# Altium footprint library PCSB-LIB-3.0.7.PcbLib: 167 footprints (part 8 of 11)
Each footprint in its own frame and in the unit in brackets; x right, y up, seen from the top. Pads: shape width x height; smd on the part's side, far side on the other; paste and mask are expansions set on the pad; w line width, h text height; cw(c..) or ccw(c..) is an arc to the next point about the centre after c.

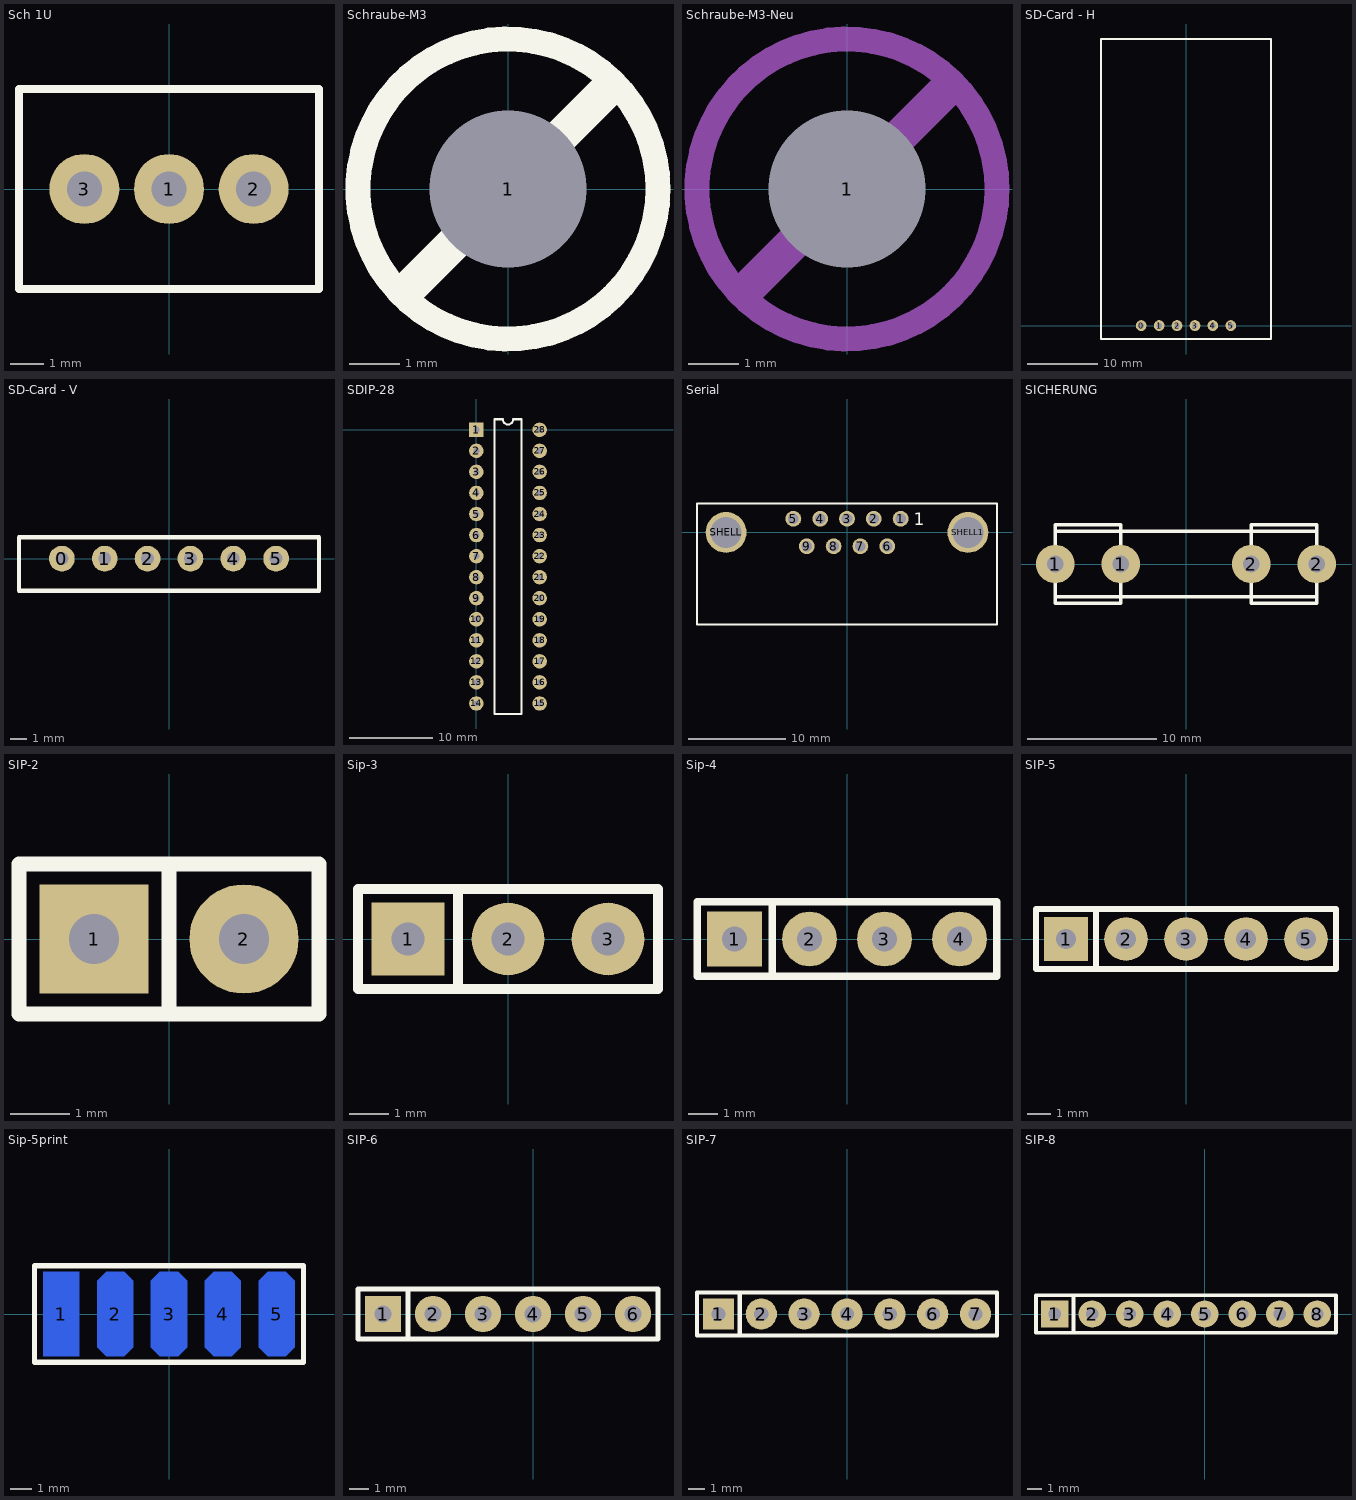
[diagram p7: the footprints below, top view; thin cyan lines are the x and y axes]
## Sch 1U [mm]
pads (3):
  round 2.1 hole 1.05: 1(0,0) 2(2.54,0) 3(-2.54,0)
Top Overlay:
  lines w0.254: -4.5,-3 4.5,-3 4.5,3 -4.5,3 -4.5,-3

## Schraube-M3 [mm] "Befestigungsschraube für Prints"
pads (1):
  round 0.75 hole 3.15 unplated: 1(0,0)
Top Overlay:
  circle w0.5: c0,0 r3
  lines w0.7: -2,-2 2,2

## Schraube-M3-Neu [mm] "Befestigungsschraube für Prints"
pads (1):
  round 0.75 hole 3.15 unplated: 1(0,0)
Mechanical 1:
  circle w0.5: c0,0 r3
  lines w0.7: -2,-2 2,2

## SD-Card - H [mil]
pads (6):
  round 60 hole 30: 0(-250,0) 1(-150,0) 2(-50,0) 3(50,0) 4(150,0) 5(250,0)
Top Overlay:
  lines w10: -475,-75 475,-75 475,1600 -475,1600 -475,-75

## SD-Card - V [mil]
pads (6):
  round 60 hole 30: 0(-250,0) 1(-150,0) 2(-50,0) 3(50,0) 4(150,0) 5(250,0)
Top Overlay:
  lines w10: -350,-75 -350,50 350,50 350,-75 -350,-75

## SDIP-28 [mm]
pads (28):
  rect 1.75x1.75 hole 0.75: 1(0,0)
  round 1.75 hole 0.75: 2(0,-2.54) 3(0,-5.08) 4(0,-7.62) 5(0,-10.16) 6(0,-12.7) 7(0,-15.24) 8(0,-17.78) 9(0,-20.32) 10(0,-22.86) 11(0,-25.4) 12(0,-27.94) 13(0,-30.48) 14(0,-33.02) 15(7.62,-33.02) 16(7.62,-30.48) 17(7.62,-27.94) 18(7.62,-25.4) 19(7.62,-22.86) 20(7.62,-20.32) 21(7.62,-17.78) 22(7.62,-15.24) 23(7.62,-12.7) 24(7.62,-10.16) 25(7.62,-7.62) 26(7.62,-5.08) 27(7.62,-2.54) 28(7.62,0)
Top Overlay:
  lines w0.254: 2.159,-34.29 2.159,1.27 3.175,1.27 ccw(c3.81,1.27) 4.445,1.27 5.461,1.27 5.461,-34.29 2.159,-34.29

## Serial [mm]
pads (11):
  round 1.635 hole 1.09: 1(5.54,1.42) 2(2.77,1.42) 3(0,1.42) 4(-2.77,1.42) 5(-5.54,1.42) 6(4.155,-1.42) 7(1.385,-1.42) 8(-1.385,-1.42) 9(-4.155,-1.42)
  round 4.216 hole 3.2: SHELL(-12.5,0) SHELL1(12.5,0)
Top Overlay:
  lines w0.2: -15.5,-9.52 15.5,-9.52 15.5,3 -15.5,3 -15.5,-9.52
  text "1" at 6.915,0.735 h1.27
Mechanical 13:
  text "1" at 6.915,0.735 h1.27

## SICHERUNG [mm]
pads (4):
  round 3 hole 1.3: 1(-10.163,0.008) 1(-5.083,0.008) 2(5.077,0.008) 2(10.157,0.008)
Top Overlay:
  lines w0.254: -10.163,-2.532 -10.163,-3.04 -5.083,-3.04 -5.083,-2.532 -5.083,2.548 -5.083,3.056 -10.163,3.056 -10.163,2.548 ; -10.163,-2.532 10.157,-2.532 ; -10.163,-2.532 -10.163,2.548 ; -10.163,2.548 10.157,2.548 ; 10.157,-2.532 10.157,-3.04 5.077,-3.04 5.077,-2.532 5.077,2.548 5.077,3.056 10.157,3.056 10.157,2.548 ; 10.157,-2.532 10.157,2.548

## SIP-2 [mm]
pads (2):
  rect 1.85x1.85 hole 0.85: 1(-1.27,0)
  round 1.85 hole 0.85: 2(1.27,0)
Top Overlay:
  lines w0.254: 0,-1.27 0,1.27 ; -2.54,-1.27 -2.54,1.27 2.54,1.27 2.54,-1.27 -2.54,-1.27

## Sip-3 [mm]
pads (3):
  rect 1.85x1.85 hole 0.85: 1(-2.54,0)
  round 1.85 hole 0.85: 2(0,0) 3(2.54,0)
Top Overlay:
  lines w0.254: -1.27,-1.27 -1.27,1.27 ; -3.81,-1.27 -3.81,1.27 3.81,1.27 3.81,-1.27 -3.81,-1.27

## Sip-4 [mm]
pads (4):
  rect 1.85x1.85 hole 0.85: 1(-3.81,0)
  round 1.85 hole 0.85: 2(-1.27,0) 3(1.27,0) 4(3.81,0)
Top Overlay:
  lines w0.254: -2.54,-1.27 -2.54,1.27 ; -5.08,-1.27 -5.08,1.27 5.08,1.27 5.08,-1.27 -5.08,-1.27

## SIP-5 [mm]
pads (5):
  rect 1.85x1.85 hole 0.85: 1(-5.08,0)
  round 1.85 hole 0.85: 2(-2.54,0) 3(0,0) 4(2.54,0) 5(5.08,0)
Top Overlay:
  lines w0.254: -3.81,-1.27 -3.81,1.27 ; -6.35,-1.27 6.35,-1.27 6.35,1.27 -6.35,1.27 -6.35,-1.27

## Sip-5print [mm]
pads (5):
  rect 1.7x4 smd far side: 1(-5.08,0)
  oct 1.7x4 smd far side: 2(-2.54,0) 3(0,0) 4(2.54,0) 5(5.08,0)
Top Overlay:
  lines w0.254: -6.35,-2.286 -6.35,2.286 6.35,2.286 6.35,-2.286 -6.35,-2.286

## SIP-6 [mm]
pads (6):
  rect 1.85x1.85 hole 0.85: 1(-7.62,0)
  round 1.85 hole 0.85: 2(-5.08,0) 3(-2.54,0) 4(0,0) 5(2.54,0) 6(5.08,0)
Top Overlay:
  lines w0.254: -6.35,-1.27 -6.35,1.27 ; -8.89,-1.27 -8.89,1.27 6.35,1.27 6.35,-1.27 -8.89,-1.27

## SIP-7 [mm]
pads (7):
  rect 1.85x1.85 hole 0.85: 1(-7.62,0)
  round 1.85 hole 0.85: 2(-5.08,0) 3(-2.54,0) 4(0,0) 5(2.54,0) 6(5.08,0) 7(7.62,0)
Top Overlay:
  lines w0.254: -6.35,-1.27 -6.35,1.27 ; -8.89,-1.27 8.89,-1.27 8.89,1.27 -8.89,1.27 -8.89,-1.27

## SIP-8 [mm]
pads (8):
  rect 1.85x1.85 hole 0.85: 1(-10.16,0)
  round 1.85 hole 0.85: 2(-7.62,0) 3(-5.08,0) 4(-2.54,0) 5(0,0) 6(2.54,0) 7(5.08,0) 8(7.62,0)
Top Overlay:
  lines w0.254: -8.89,-1.27 -8.89,1.27 ; -11.43,-1.27 -11.43,1.27 8.89,1.27 8.89,-1.27 -11.43,-1.27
